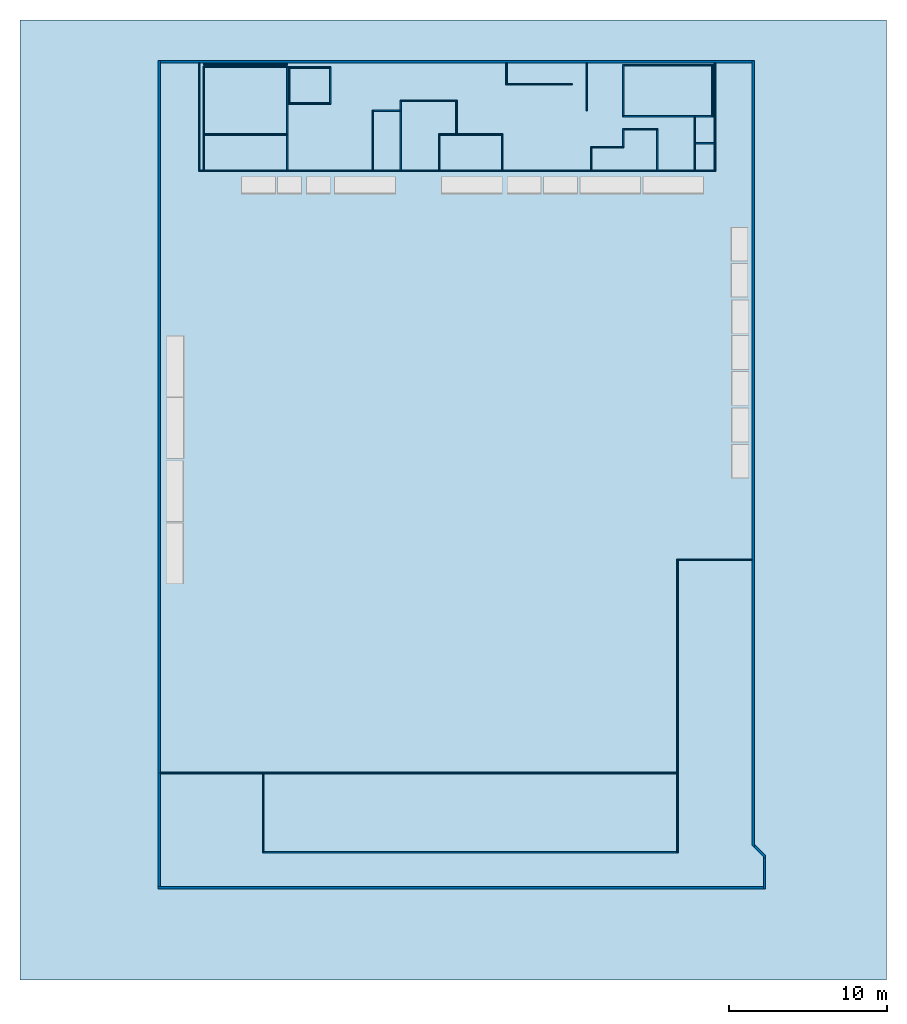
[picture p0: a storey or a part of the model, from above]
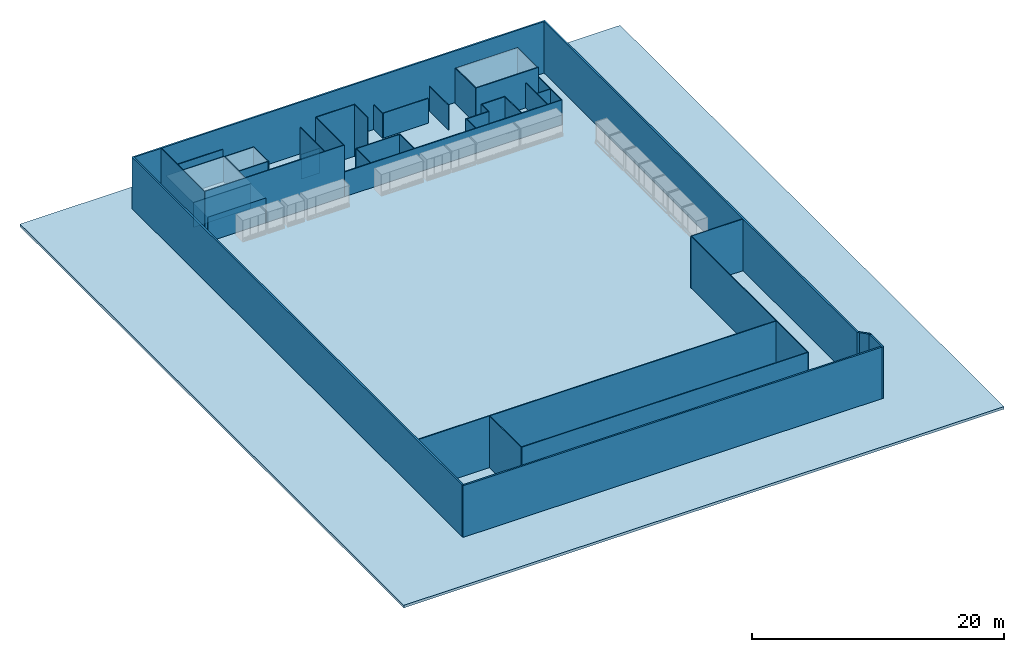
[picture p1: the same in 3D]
Properties of the parts of a building model (IFC2X3)

# File
Description: ViewDefinition [CoordinationView_V2.0]
File name: 0001
Time: 2023-11-19T21:42:35
Written by: The EXPRESS Data Manager Version 5.02.0100.07 : 28 Aug 2013
Made in: 20190327_2315(x64) - Exporter 20.0.0.377 - Alternate UI 20.0.0.377
Comment: STEP Physical File produced by: The EXPRESS Data Manager Version 5.02.0100.07 : 28 Aug 2013 * Module: EDMstepFileFactory/EDMstandAlone * Creation date: Sun Nov 19 21:42:35 2023 * Host: DESKTOP-PVHMC9R * Database: C:\Users\Jacques\AppData\Local\Temp\8564e2f0-3d8d-45c8-9f77-5ed3639c3e4c\52fad7cf-c440-4692-a7b8-1f0c481c9a44\ifc * Database version: 5507 * Database creation date: Sun Nov 19 21:42:21 2023 * Schema: IFC2X3 * Model: DataRepository.ifc * Model creation date: Sun Nov 19 21:42:30 2023 * Header model: DataRepository.ifc_HeaderModel * Header model creation date: Sun Nov 19 21:42:30 2023 * EDMuser: sdai-user * EDMgroup: sdai-group * License ID and type: 5605 : Permanent license. Expiry date: * EDMstepFileFactory options: 020000

# IfcProject, 0001
LongName: Nom du projet; Phase: Etat du projet

# IfcSite, Default
RefLatitude: 48, 52, 0, 117187; RefLongitude: 2, 19, 59, 880409; RefElevation: 0 m

# IfcBuilding
Pset_BuildingCommon - NumberOfStoreys: 1

# IfcBuildingStorey: Niveau:Ligne du Niveau, Niveau 0
LongName: Niveau 0; Elevation: 1.49234 m

# IfcBuildingElementProxy: 1575mm (2)
In: Niveau 0
Type - Material: Verre, Métal - Chrome, Peinture - Blanc, Plastique - Gris foncé
Type - Pset_BuildingElementProxyCommon - Reference: 1575mm
Type - Pset_QuantityTakeOff - Reference: 1575mm
Pset_BuildingElementProxyCommon - sets with these values: 2
Name (Congélateur - Vertical deux portes:1575mm:...)
267343
267979

# IfcBuildingElementProxy: 2200mm (10)
In: Niveau 0
Type - Material: Métal - Chrome, Verre, Peinture - Blanc, Plastique - Gris foncé
Type - Pset_BuildingElementProxyCommon - Reference: 2200mm
Type - Pset_QuantityTakeOff - Reference: 2200mm
Pset_BuildingElementProxyCommon - sets with these values: 2
Name (Congélateur - Vertical trois portes:2200mm:...)
260063
261097
261135
261146
261157
261168
261646
266308
266319
268169

# IfcBuildingElementProxy: Longueur 3910 mm (8)
In: Niveau 0
Type - Material: Métal - Chrome, Verre, Peinture - Blanc, Peinture - Gris foncé
Type - Pset_BuildingElementProxyCommon - Reference: Longueur 3910 mm
Type - Pset_QuantityTakeOff - Reference: Longueur 3910 mm
Pset_BuildingElementProxyCommon - sets with these values: 2
Name (Congélateur - Vertical cinq portes:Longueur 3910 mm:...)
262822
262833
262844
266188
266210
266221
266232
266341

# IfcSlab: Sol:Dalle en béton - 250 mm, Sol:Dalle en béton - 250 mm:269955
In: Niveau 0
Type - PredefinedType: FLOOR; Material: Maçonnerie - Béton 0.25 m
Type - Pset_QuantityTakeOff - Reference: Dalle en béton - 250 mm
Type - Pset_ReinforcementBarPitchOfSlab - Reference: Dalle en béton - 250 mm
Type - Pset_SlabCommon - IsExternal: no; Reference: Dalle en béton - 250 mm
Pset_QuantityTakeOff - sets with these values: 2
Pset_SlabCommon - LoadBearing: no; PitchAngle: 0 deg

# IfcSlab: Sol:Dalle en béton - 80 mm (4)
In: Niveau 0
Type - PredefinedType: FLOOR; Material: Maçonnerie - Béton 0.08 m
Type - Pset_QuantityTakeOff - Reference: Dalle en béton - 80 mm
Type - Pset_ReinforcementBarPitchOfSlab - Reference: Dalle en béton - 80 mm
Type - Pset_SlabCommon - IsExternal: no; Reference: Dalle en béton - 80 mm
Pset_QuantityTakeOff - sets with these values: 2
Pset_SlabCommon - LoadBearing: no; PitchAngle: 0 deg
Name (Sol:Dalle en béton - 80 mm:...)
265429
265668
265878
269155

# IfcWallStandardCase: Mur de base:Générique - Ext. 150 mm (6)
In: Niveau 0
Type - PredefinedType: STANDARD; Material: Mur par défaut 0.15 m
Type - Pset_QuantityTakeOff - Reference: Générique - Ext. 150 mm
Type - Pset_ReinforcementBarPitchOfWall - Reference: Générique - Ext. 150 mm
Type - Pset_WallCommon - IsExternal: no; Reference: Générique - Ext. 150 mm
Pset_QuantityTakeOff - sets with these values: 2
Pset_WallCommon - ExtendToStructure: no; LoadBearing: no; IsExternal: yes
Name (Mur de base:Générique - Ext. 150 mm:...)
256306
256318
256335
256386
256462
258860

# IfcWallStandardCase: Mur de base:Générique - Int. 70 mm (41)
In: Niveau 0
Type - PredefinedType: STANDARD; Material: Mur par défaut 0.07 m
Type - Pset_QuantityTakeOff - Reference: Générique - Int. 70 mm
Type - Pset_ReinforcementBarPitchOfWall - Reference: Générique - Int. 70 mm
Type - Pset_WallCommon - Reference: Générique - Int. 70 mm; IsExternal: no
Pset_QuantityTakeOff - sets with these values: 2
Name (Mur de base:Générique - Int. 70 mm:...) | ExtendToStructure | LoadBearing
255928 | no | no
255999 | no | no
256032 | no | no
256070 | no | no
256755 | no | yes
256916 | no | yes
257037 | no | yes
257282 | no | yes
257503 | no | yes
263152 | no | yes
263323 | no | yes
263392 | no | yes
263469 | no | yes
263576 | no | yes
263668 | no | yes
263731 | no | yes
263802 | no | yes
264155 | no | yes
264218 | no | yes
264249 | no | yes
264320 | no | yes
264379 | no | yes
264430 | no | yes
264527 | yes | yes
264612 | no | yes
264651 | no | yes
264888 | no | yes
265014 | no | yes
265069 | no | yes
265146 | no | yes
265185 | no | yes
265254 | no | yes
265305 | no | yes
265368 | no | yes
268249 | no | yes
268300 | no | yes
268385 | no | yes
268438 | no | yes
268519 | no | yes
268804 | yes | yes
268962 | yes | yes
